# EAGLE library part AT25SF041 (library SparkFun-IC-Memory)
AT25SF041 4Mb Serial Flash Memory 104MHz, SPI, 8-SOIC Datasheet SparkFun Products: SparkFun ESP8266 Thing SparkFun ESP8266 Thing - Dev Board

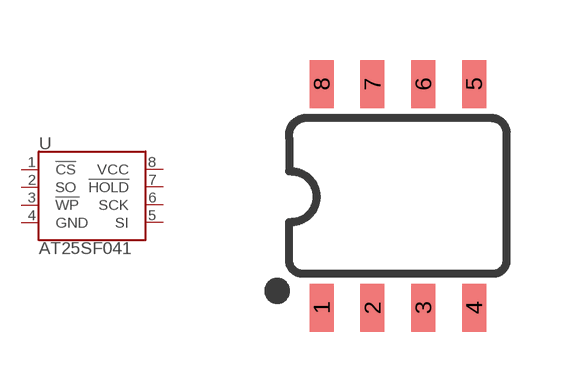
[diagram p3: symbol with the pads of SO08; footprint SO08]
Designator prefix U

## AT25SF041 (PROD_ID: IC-12455; VALUE: 4MB Flash)  [SO08]
1  !CS
2  SO
3  !WP
4  GND
5  SI
6  SCK
7  !HOLD
8  VCC

## Footprint SO08 (pad centres in mm)
SOIC, 0.15 inch width
smd 0.6 x 1.2: 1 -1.905,-2.8; 2 -0.635,-2.8; 3 0.635,-2.8; 4 1.905,-2.8; 5 1.905,2.8; 6 0.635,2.8; 7 -0.635,2.8; 8 -1.905,2.8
